VERSION 5.7 ;
  NOWIREEXTENSIONATPIN ON ;
  DIVIDERCHAR "/" ;
  BUSBITCHARS "[]" ;
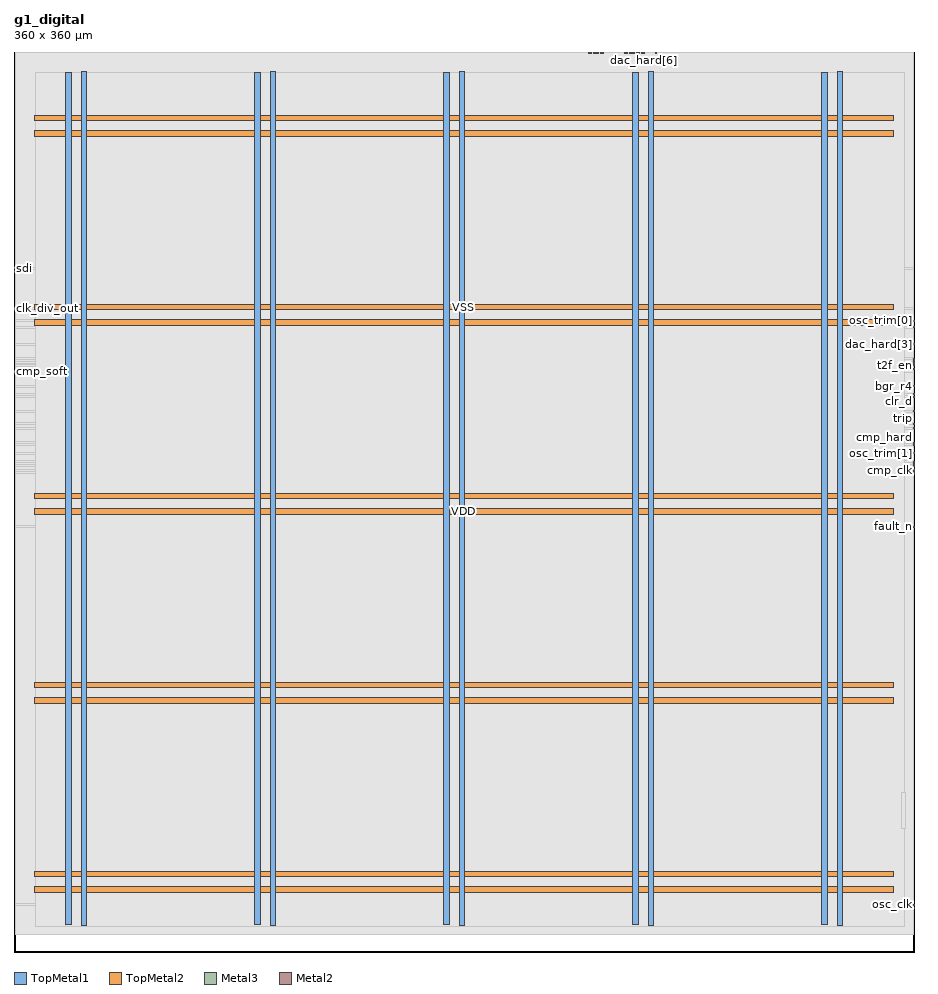
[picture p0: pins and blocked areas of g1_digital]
MACRO g1_digital
  CLASS BLOCK ;
  FOREIGN g1_digital ;
  ORIGIN 0.000 0.000 ;
  SIZE 360.000 BY 360.000 ;
  PIN VDD
    DIRECTION INOUT ;
    USE POWER ;
    PORT
      LAYER TopMetal1 ;
        RECT 20.660 11.120 22.860 351.760 ;
    END
    PORT
      LAYER TopMetal1 ;
        RECT 96.260 11.120 98.460 351.760 ;
    END
    PORT
      LAYER TopMetal1 ;
        RECT 171.860 11.120 174.060 351.760 ;
    END
    PORT
      LAYER TopMetal1 ;
        RECT 247.460 11.120 249.660 351.760 ;
    END
    PORT
      LAYER TopMetal1 ;
        RECT 323.060 11.120 325.260 351.760 ;
    END
    PORT
      LAYER TopMetal2 ;
        RECT 8.160 23.840 351.840 26.040 ;
    END
    PORT
      LAYER TopMetal2 ;
        RECT 8.160 99.440 351.840 101.640 ;
    END
    PORT
      LAYER TopMetal2 ;
        RECT 8.160 175.040 351.840 177.240 ;
    END
    PORT
      LAYER TopMetal2 ;
        RECT 8.160 250.640 351.840 252.840 ;
    END
    PORT
      LAYER TopMetal2 ;
        RECT 8.160 326.240 351.840 328.440 ;
    END
  END VDD
  PIN VSS
    DIRECTION INOUT ;
    USE GROUND ;
    PORT
      LAYER TopMetal1 ;
        RECT 26.860 10.710 29.060 352.170 ;
    END
    PORT
      LAYER TopMetal1 ;
        RECT 102.460 10.710 104.660 352.170 ;
    END
    PORT
      LAYER TopMetal1 ;
        RECT 178.060 10.710 180.260 352.170 ;
    END
    PORT
      LAYER TopMetal1 ;
        RECT 253.660 10.710 255.860 352.170 ;
    END
    PORT
      LAYER TopMetal1 ;
        RECT 329.260 10.710 331.460 352.170 ;
    END
    PORT
      LAYER TopMetal2 ;
        RECT 8.160 30.040 351.840 32.240 ;
    END
    PORT
      LAYER TopMetal2 ;
        RECT 8.160 105.640 351.840 107.840 ;
    END
    PORT
      LAYER TopMetal2 ;
        RECT 8.160 181.240 351.840 183.440 ;
    END
    PORT
      LAYER TopMetal2 ;
        RECT 8.160 256.840 351.840 259.040 ;
    END
    PORT
      LAYER TopMetal2 ;
        RECT 8.160 332.440 351.840 334.640 ;
    END
  END VSS
  PIN bgr_r4
    DIRECTION OUTPUT ;
    USE SIGNAL ;
    ANTENNADIFFAREA 0.708600 ;
    PORT
      LAYER Metal3 ;
        RECT 359.600 226.180 360.000 226.580 ;
    END
  END bgr_r4
  PIN clk_div_out
    DIRECTION OUTPUT ;
    USE SIGNAL ;
    ANTENNADIFFAREA 0.708600 ;
    PORT
      LAYER Metal3 ;
        RECT 0.000 257.260 0.400 257.660 ;
    END
  END clk_div_out
  PIN clr_d
    DIRECTION OUTPUT ;
    USE SIGNAL ;
    ANTENNADIFFAREA 0.708600 ;
    PORT
      LAYER Metal3 ;
        RECT 359.600 222.820 360.000 223.220 ;
    END
  END clr_d
  PIN cmp_clk
    DIRECTION OUTPUT ;
    USE SIGNAL ;
    ANTENNADIFFAREA 0.708600 ;
    PORT
      LAYER Metal3 ;
        RECT 359.600 192.580 360.000 192.980 ;
    END
  END cmp_clk
  PIN cmp_hard
    DIRECTION INPUT ;
    USE SIGNAL ;
    ANTENNAGATEAREA 0.180700 ;
    PORT
      LAYER Metal3 ;
        RECT 359.600 202.660 360.000 203.060 ;
    END
  END cmp_hard
  PIN cmp_soft
    DIRECTION INPUT ;
    USE SIGNAL ;
    ANTENNAGATEAREA 0.180700 ;
    PORT
      LAYER Metal3 ;
        RECT 0.000 232.060 0.400 232.460 ;
    END
  END cmp_soft
  PIN dac_hard[0]
    DIRECTION OUTPUT ;
    USE SIGNAL ;
    ANTENNADIFFAREA 0.708600 ;
    PORT
      LAYER Metal2 ;
        RECT 232.600 359.600 233.000 360.000 ;
    END
  END dac_hard[0]
  PIN dac_hard[1]
    DIRECTION OUTPUT ;
    USE SIGNAL ;
    ANTENNADIFFAREA 0.708600 ;
    PORT
      LAYER Metal2 ;
        RECT 231.640 359.600 232.040 360.000 ;
    END
  END dac_hard[1]
  PIN dac_hard[2]
    DIRECTION OUTPUT ;
    USE SIGNAL ;
    ANTENNADIFFAREA 0.708600 ;
    PORT
      LAYER Metal2 ;
        RECT 229.720 359.600 230.120 360.000 ;
    END
  END dac_hard[2]
  PIN dac_hard[3]
    DIRECTION OUTPUT ;
    USE SIGNAL ;
    ANTENNADIFFAREA 0.708600 ;
    PORT
      LAYER Metal3 ;
        RECT 359.600 242.980 360.000 243.380 ;
    END
  END dac_hard[3]
  PIN dac_hard[4]
    DIRECTION OUTPUT ;
    USE SIGNAL ;
    ANTENNADIFFAREA 0.708600 ;
    PORT
      LAYER Metal2 ;
        RECT 248.920 359.600 249.320 360.000 ;
    END
  END dac_hard[4]
  PIN dac_hard[5]
    DIRECTION OUTPUT ;
    USE SIGNAL ;
    ANTENNADIFFAREA 0.708600 ;
    PORT
      LAYER Metal2 ;
        RECT 246.040 359.600 246.440 360.000 ;
    END
  END dac_hard[5]
  PIN dac_hard[6]
    DIRECTION OUTPUT ;
    USE SIGNAL ;
    ANTENNADIFFAREA 0.708600 ;
    PORT
      LAYER Metal2 ;
        RECT 251.800 359.600 252.200 360.000 ;
    END
  END dac_hard[6]
  PIN dac_hard[7]
    DIRECTION OUTPUT ;
    USE SIGNAL ;
    ANTENNADIFFAREA 0.708600 ;
    PORT
      LAYER Metal2 ;
        RECT 245.080 359.600 245.480 360.000 ;
    END
  END dac_hard[7]
  PIN dac_soft[0]
    DIRECTION OUTPUT ;
    USE SIGNAL ;
    ANTENNADIFFAREA 0.708600 ;
    PORT
      LAYER Metal2 ;
        RECT 235.480 359.600 235.880 360.000 ;
    END
  END dac_soft[0]
  PIN dac_soft[1]
    DIRECTION OUTPUT ;
    USE SIGNAL ;
    ANTENNADIFFAREA 0.708600 ;
    PORT
      LAYER Metal2 ;
        RECT 233.560 359.600 233.960 360.000 ;
    END
  END dac_soft[1]
  PIN dac_soft[2]
    DIRECTION OUTPUT ;
    USE SIGNAL ;
    ANTENNADIFFAREA 0.708600 ;
    PORT
      LAYER Metal2 ;
        RECT 230.680 359.600 231.080 360.000 ;
    END
  END dac_soft[2]
  PIN dac_soft[3]
    DIRECTION OUTPUT ;
    USE SIGNAL ;
    ANTENNADIFFAREA 0.708600 ;
    PORT
      LAYER Metal2 ;
        RECT 234.520 359.600 234.920 360.000 ;
    END
  END dac_soft[3]
  PIN dac_soft[4]
    DIRECTION OUTPUT ;
    USE SIGNAL ;
    ANTENNADIFFAREA 0.708600 ;
    PORT
      LAYER Metal2 ;
        RECT 250.840 359.600 251.240 360.000 ;
    END
  END dac_soft[4]
  PIN dac_soft[5]
    DIRECTION OUTPUT ;
    USE SIGNAL ;
    ANTENNADIFFAREA 0.708600 ;
    PORT
      LAYER Metal2 ;
        RECT 247.960 359.600 248.360 360.000 ;
    END
  END dac_soft[5]
  PIN dac_soft[6]
    DIRECTION OUTPUT ;
    USE SIGNAL ;
    ANTENNADIFFAREA 0.708600 ;
    PORT
      LAYER Metal2 ;
        RECT 249.880 359.600 250.280 360.000 ;
    END
  END dac_soft[6]
  PIN dac_soft[7]
    DIRECTION OUTPUT ;
    USE SIGNAL ;
    ANTENNADIFFAREA 0.708600 ;
    PORT
      LAYER Metal2 ;
        RECT 247.000 359.600 247.400 360.000 ;
    END
  END dac_soft[7]
  PIN en
    DIRECTION INPUT ;
    USE SIGNAL ;
    ANTENNAGATEAREA 0.180700 ;
    PORT
      LAYER Metal3 ;
        RECT 359.600 235.420 360.000 235.820 ;
    END
  END en
  PIN fast_en
    DIRECTION OUTPUT ;
    USE SIGNAL ;
    ANTENNADIFFAREA 0.708600 ;
    PORT
      LAYER Metal3 ;
        RECT 359.600 194.260 360.000 194.660 ;
    END
  END fast_en
  PIN fault_n
    DIRECTION OUTPUT ;
    USE SIGNAL ;
    ANTENNADIFFAREA 0.708600 ;
    PORT
      LAYER Metal3 ;
        RECT 359.600 169.900 360.000 170.300 ;
    END
  END fault_n
  PIN gate_en
    DIRECTION OUTPUT ;
    USE SIGNAL ;
    ANTENNADIFFAREA 0.708600 ;
    PORT
      LAYER Metal3 ;
        RECT 359.600 236.260 360.000 236.660 ;
    END
  END gate_en
  PIN osc_clk
    DIRECTION INPUT ;
    USE SIGNAL ;
    ANTENNAGATEAREA 1.450800 ;
    PORT
      LAYER Metal3 ;
        RECT 359.600 18.700 360.000 19.100 ;
    END
  END osc_clk
  PIN osc_en
    DIRECTION OUTPUT ;
    USE SIGNAL ;
    ANTENNADIFFAREA 0.708600 ;
    PORT
      LAYER Metal3 ;
        RECT 359.600 191.740 360.000 192.140 ;
    END
  END osc_en
  PIN osc_trim[0]
    DIRECTION OUTPUT ;
    USE SIGNAL ;
    ANTENNADIFFAREA 0.708600 ;
    PORT
      LAYER Metal3 ;
        RECT 359.600 252.220 360.000 252.620 ;
    END
  END osc_trim[0]
  PIN osc_trim[1]
    DIRECTION OUTPUT ;
    USE SIGNAL ;
    ANTENNADIFFAREA 0.708600 ;
    PORT
      LAYER Metal3 ;
        RECT 359.600 199.300 360.000 199.700 ;
    END
  END osc_trim[1]
  PIN osc_trim[2]
    DIRECTION OUTPUT ;
    USE SIGNAL ;
    ANTENNADIFFAREA 0.708600 ;
    PORT
      LAYER Metal3 ;
        RECT 359.600 249.700 360.000 250.100 ;
    END
  END osc_trim[2]
  PIN osc_trim[3]
    DIRECTION OUTPUT ;
    USE SIGNAL ;
    ANTENNADIFFAREA 0.708600 ;
    PORT
      LAYER Metal3 ;
        RECT 359.600 195.100 360.000 195.500 ;
    END
  END osc_trim[3]
  PIN por_n
    DIRECTION INPUT ;
    USE SIGNAL ;
    ANTENNAGATEAREA 0.180700 ;
    PORT
      LAYER Metal3 ;
        RECT 359.600 237.100 360.000 237.500 ;
    END
  END por_n
  PIN sclk
    DIRECTION INPUT ;
    USE SIGNAL ;
    ANTENNAGATEAREA 2.901600 ;
    PORT
      LAYER Metal2 ;
        RECT 244.120 359.600 244.520 360.000 ;
    END
  END sclk
  PIN sdi
    DIRECTION INPUT ;
    USE SIGNAL ;
    ANTENNAGATEAREA 0.180700 ;
    PORT
      LAYER Metal3 ;
        RECT 0.000 273.220 0.400 273.620 ;
    END
  END sdi
  PIN sdo
    DIRECTION OUTPUT ;
    USE SIGNAL ;
    ANTENNADIFFAREA 0.708600 ;
    PORT
      LAYER Metal2 ;
        RECT 256.600 359.600 257.000 360.000 ;
    END
  END sdo
  PIN t2f_en
    DIRECTION OUTPUT ;
    USE SIGNAL ;
    ANTENNADIFFAREA 0.708600 ;
    PORT
      LAYER Metal3 ;
        RECT 359.600 234.580 360.000 234.980 ;
    END
  END t2f_en
  PIN t2f_mode
    DIRECTION OUTPUT ;
    USE SIGNAL ;
    ANTENNADIFFAREA 0.708600 ;
    PORT
      LAYER Metal3 ;
        RECT 359.600 232.900 360.000 233.300 ;
    END
  END t2f_mode
  PIN trip
    DIRECTION OUTPUT ;
    USE SIGNAL ;
    ANTENNADIFFAREA 0.708600 ;
    PORT
      LAYER Metal3 ;
        RECT 359.600 216.100 360.000 216.500 ;
    END
  END trip
  PIN trip_cause[0]
    DIRECTION OUTPUT ;
    USE SIGNAL ;
    ANTENNADIFFAREA 0.708600 ;
    PORT
      LAYER Metal3 ;
        RECT 359.600 209.380 360.000 209.780 ;
    END
  END trip_cause[0]
  PIN trip_cause[1]
    DIRECTION OUTPUT ;
    USE SIGNAL ;
    ANTENNADIFFAREA 0.708600 ;
    PORT
      LAYER Metal3 ;
        RECT 359.600 211.060 360.000 211.460 ;
    END
  END trip_cause[1]
  PIN trip_d
    DIRECTION OUTPUT ;
    USE SIGNAL ;
    ANTENNADIFFAREA 0.708600 ;
    PORT
      LAYER Metal3 ;
        RECT 359.600 221.980 360.000 222.380 ;
    END
  END trip_d
  PIN trip_set_sel
    DIRECTION OUTPUT ;
    USE SIGNAL ;
    ANTENNADIFFAREA 0.708600 ;
    PORT
      LAYER Metal3 ;
        RECT 359.600 203.500 360.000 203.900 ;
    END
  END trip_set_sel
  PIN tripped
    DIRECTION INPUT ;
    USE SIGNAL ;
    ANTENNAGATEAREA 0.180700 ;
    PORT
      LAYER Metal3 ;
        RECT 359.600 195.940 360.000 196.340 ;
    END
  END tripped
  OBS
      LAYER GatPoly ;
        RECT 8.160 11.190 351.840 351.690 ;
      LAYER Metal1 ;
        RECT 8.160 11.120 351.840 351.760 ;
      LAYER Metal2 ;
        RECT 7.575 359.390 229.510 359.665 ;
        RECT 230.330 359.390 230.470 359.665 ;
        RECT 231.290 359.390 231.430 359.665 ;
        RECT 232.250 359.390 232.390 359.665 ;
        RECT 233.210 359.390 233.350 359.665 ;
        RECT 234.170 359.390 234.310 359.665 ;
        RECT 235.130 359.390 235.270 359.665 ;
        RECT 236.090 359.390 243.910 359.665 ;
        RECT 244.730 359.390 244.870 359.665 ;
        RECT 245.690 359.390 245.830 359.665 ;
        RECT 246.650 359.390 246.790 359.665 ;
        RECT 247.610 359.390 247.750 359.665 ;
        RECT 248.570 359.390 248.710 359.665 ;
        RECT 249.530 359.390 249.670 359.665 ;
        RECT 250.490 359.390 250.630 359.665 ;
        RECT 251.450 359.390 251.590 359.665 ;
        RECT 252.410 359.390 256.390 359.665 ;
        RECT 257.210 359.390 359.625 359.665 ;
        RECT 7.575 6.995 359.625 359.390 ;
      LAYER Metal3 ;
        RECT 0.400 273.830 359.665 359.620 ;
        RECT 0.610 273.010 359.665 273.830 ;
        RECT 0.400 257.870 359.665 273.010 ;
        RECT 0.610 257.050 359.665 257.870 ;
        RECT 0.400 252.830 359.665 257.050 ;
        RECT 0.400 252.010 359.390 252.830 ;
        RECT 0.400 250.310 359.665 252.010 ;
        RECT 0.400 249.490 359.390 250.310 ;
        RECT 0.400 243.590 359.665 249.490 ;
        RECT 0.400 242.770 359.390 243.590 ;
        RECT 0.400 237.710 359.665 242.770 ;
        RECT 0.400 236.890 359.390 237.710 ;
        RECT 0.400 236.870 359.665 236.890 ;
        RECT 0.400 236.050 359.390 236.870 ;
        RECT 0.400 236.030 359.665 236.050 ;
        RECT 0.400 235.210 359.390 236.030 ;
        RECT 0.400 235.190 359.665 235.210 ;
        RECT 0.400 234.370 359.390 235.190 ;
        RECT 0.400 233.510 359.665 234.370 ;
        RECT 0.400 232.690 359.390 233.510 ;
        RECT 0.400 232.670 359.665 232.690 ;
        RECT 0.610 231.850 359.665 232.670 ;
        RECT 0.400 226.790 359.665 231.850 ;
        RECT 0.400 225.970 359.390 226.790 ;
        RECT 0.400 223.430 359.665 225.970 ;
        RECT 0.400 222.610 359.390 223.430 ;
        RECT 0.400 222.590 359.665 222.610 ;
        RECT 0.400 221.770 359.390 222.590 ;
        RECT 0.400 216.710 359.665 221.770 ;
        RECT 0.400 215.890 359.390 216.710 ;
        RECT 0.400 211.670 359.665 215.890 ;
        RECT 0.400 210.850 359.390 211.670 ;
        RECT 0.400 209.990 359.665 210.850 ;
        RECT 0.400 209.170 359.390 209.990 ;
        RECT 0.400 204.110 359.665 209.170 ;
        RECT 0.400 203.290 359.390 204.110 ;
        RECT 0.400 203.270 359.665 203.290 ;
        RECT 0.400 202.450 359.390 203.270 ;
        RECT 0.400 199.910 359.665 202.450 ;
        RECT 0.400 199.090 359.390 199.910 ;
        RECT 0.400 196.550 359.665 199.090 ;
        RECT 0.400 195.730 359.390 196.550 ;
        RECT 0.400 195.710 359.665 195.730 ;
        RECT 0.400 194.890 359.390 195.710 ;
        RECT 0.400 194.870 359.665 194.890 ;
        RECT 0.400 194.050 359.390 194.870 ;
        RECT 0.400 193.190 359.665 194.050 ;
        RECT 0.400 192.370 359.390 193.190 ;
        RECT 0.400 192.350 359.665 192.370 ;
        RECT 0.400 191.530 359.390 192.350 ;
        RECT 0.400 170.510 359.665 191.530 ;
        RECT 0.400 169.690 359.390 170.510 ;
        RECT 0.400 19.310 359.665 169.690 ;
        RECT 0.400 18.490 359.390 19.310 ;
        RECT 0.400 7.040 359.665 18.490 ;
      LAYER Metal4 ;
        RECT 8.540 10.355 355.305 351.685 ;
      LAYER Metal5 ;
        RECT 20.795 10.400 356.190 351.850 ;
      LAYER TopMetal1 ;
        RECT 355.060 49.580 356.700 63.820 ;
  END
END g1_digital
END LIBRARY

